
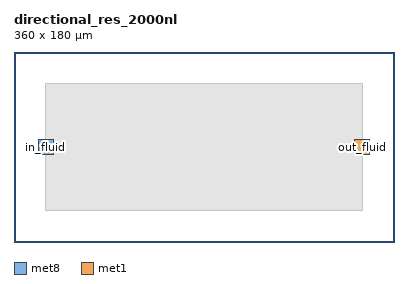
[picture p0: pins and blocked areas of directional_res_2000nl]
MACRO directional_res_2000nl
  CLASS CORE ;
  ORIGIN  0 0 ;
  FOREIGN directional_res_2000nl 0 0 ;
  SIZE 360 BY 180 ;
  SYMMETRY X Y ;
  SITE CoreSite ;
  PIN in_fluid
    DIRECTION INPUT ;
    USE SIGNAL ;
    PORT
      LAYER met8 ;
        RECT 23 83 37 97 ;
    END
  END in_fluid
  PIN out_fluid
    DIRECTION OUTPUT ;
    USE SIGNAL ;
    PORT
      LAYER met1 ;
        RECT 323 83 337 97 ;
    END
  END out_fluid
  OBS
    LAYER met1 ;
      RECT 30 30 330 150 ;
    LAYER met2 ;
      RECT 30 30 330 150 ;
    LAYER met3 ;
      RECT 30 30 330 150 ;
    LAYER met4 ;
      RECT 30 30 330 150 ;
    LAYER met5 ;
      RECT 30 30 330 150 ;
    LAYER met6 ;
      RECT 30 30 330 150 ;
    LAYER met7 ;
      RECT 30 30 330 150 ;
    LAYER met8 ;
      RECT 30 30 330 150 ;
    LAYER met9 ;
      RECT 30 30 330 150 ;
  END
  PROPERTY CatenaDesignType "deviceLevel" ;
END directional_res_2000nl
